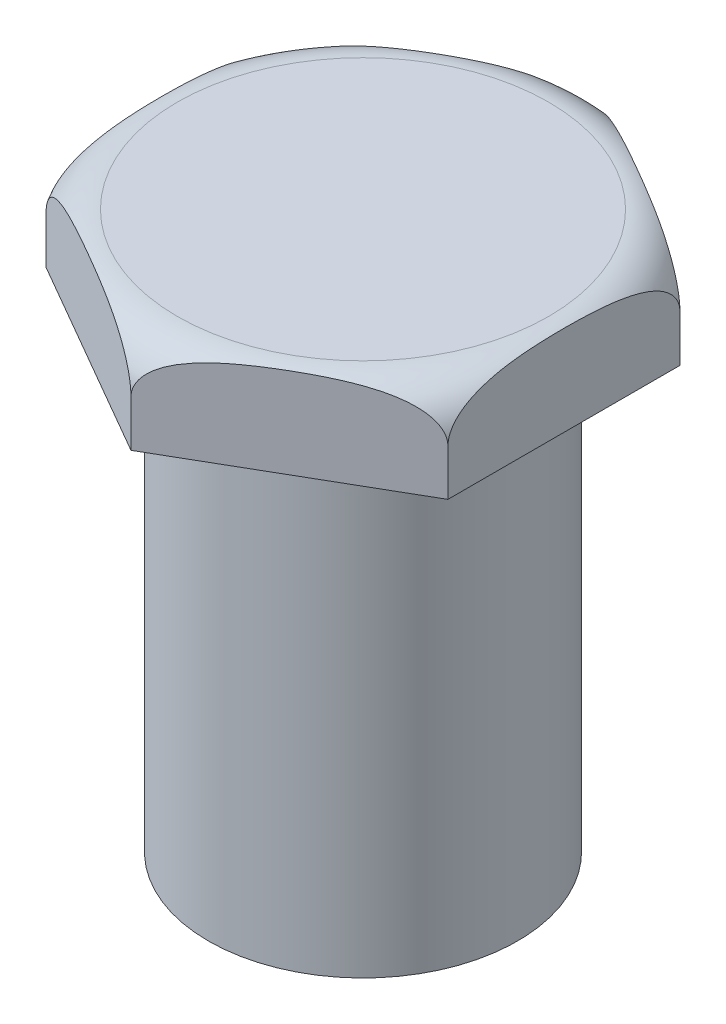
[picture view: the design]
ISO-10303-21;
HEADER;
FILE_DESCRIPTION(('STEP AP214'),'2;1');
FILE_NAME('part.step','',(''),(''),'','','');
FILE_SCHEMA(('AUTOMOTIVE_DESIGN { 1 0 10303 214 1 1 1 1 }'));
ENDSEC;
DATA;
#1=APPLICATION_CONTEXT('core data for automotive mechanical design processes');
#2=APPLICATION_PROTOCOL_DEFINITION('international standard','automotive_design',2000,#1);
#3=PRODUCT_CONTEXT('',#1,'mechanical');
#4=PRODUCT('Part','Part','',(#3));
#5=PRODUCT_RELATED_PRODUCT_CATEGORY('part','',(#4));
#6=PRODUCT_DEFINITION_FORMATION('','',#4);
#7=PRODUCT_DEFINITION_CONTEXT('part definition',#1,'design');
#8=PRODUCT_DEFINITION('design','',#6,#7);
#9=PRODUCT_DEFINITION_SHAPE('','',#8);
#10=(LENGTH_UNIT() NAMED_UNIT(*) SI_UNIT(.MILLI.,.METRE.));
#11=(NAMED_UNIT(*) PLANE_ANGLE_UNIT() SI_UNIT($,.RADIAN.));
#12=(NAMED_UNIT(*) SI_UNIT($,.STERADIAN.) SOLID_ANGLE_UNIT());
#13=UNCERTAINTY_MEASURE_WITH_UNIT(LENGTH_MEASURE(1.E-05),#10,'distance_accuracy_value','');
#14=(GEOMETRIC_REPRESENTATION_CONTEXT(3) GLOBAL_UNCERTAINTY_ASSIGNED_CONTEXT((#13)) GLOBAL_UNIT_ASSIGNED_CONTEXT((#10,
#11,#12)) REPRESENTATION_CONTEXT('',''));
#15=CARTESIAN_POINT('',(0.,0.,0.));
#16=DIRECTION('',(0.,0.,1.));
#17=DIRECTION('',(1.,0.,0.));
#18=AXIS2_PLACEMENT_3D('',#15,#16,#17);
#19=CARTESIAN_POINT('',(0.,15.,0.));
#20=DIRECTION('',(0.,-1.,0.));
#21=DIRECTION('',(0.,0.,-1.));
#22=AXIS2_PLACEMENT_3D('',#19,#20,#21);
#23=CYLINDRICAL_SURFACE('',#22,5.);
#24=CARTESIAN_POINT('',(0.,15.,0.));
#25=DIRECTION('',(0.,1.,0.));
#26=DIRECTION('',(0.,0.,1.));
#27=AXIS2_PLACEMENT_3D('',#24,#25,#26);
#28=CIRCLE('',#27,5.);
#29=CARTESIAN_POINT('',(0.,15.,5.));
#30=VERTEX_POINT('',#29);
#31=EDGE_CURVE('E11',#30,#30,#28,.T.);
#32=ORIENTED_EDGE('',*,*,#31,.F.);
#33=EDGE_LOOP('',(#32));
#34=FACE_BOUND('',#33,.T.);
#35=CARTESIAN_POINT('',(0.,0.,0.));
#36=DIRECTION('',(0.,1.,0.));
#37=DIRECTION('',(0.,0.,1.));
#38=AXIS2_PLACEMENT_3D('',#35,#36,#37);
#39=CIRCLE('',#38,5.);
#40=CARTESIAN_POINT('',(0.,0.,5.));
#41=VERTEX_POINT('',#40);
#42=EDGE_CURVE('E39',#41,#41,#39,.T.);
#43=ORIENTED_EDGE('',*,*,#42,.T.);
#44=EDGE_LOOP('',(#43));
#45=FACE_BOUND('',#44,.T.);
#46=ADVANCED_FACE('F32',(#34,#45),#23,.T.);
#47=CARTESIAN_POINT('',(0.,0.,0.));
#48=DIRECTION('',(0.,1.,0.));
#49=DIRECTION('',(0.,0.,1.));
#50=AXIS2_PLACEMENT_3D('',#47,#48,#49);
#51=PLANE('',#50);
#52=ORIENTED_EDGE('',*,*,#42,.F.);
#53=EDGE_LOOP('',(#52));
#54=FACE_BOUND('',#53,.T.);
#55=ADVANCED_FACE('F118',(#54),#51,.F.);
#56=CARTESIAN_POINT('',(0.,15.,7.50555349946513));
#57=DIRECTION('',(0.,1.,0.));
#58=DIRECTION('',(0.,0.,1.));
#59=AXIS2_PLACEMENT_3D('',#56,#57,#58);
#60=PLANE('',#59);
#61=DIRECTION('',(0.866025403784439,0.,0.5));
#62=VECTOR('',#61,1.);
#63=CARTESIAN_POINT('',(-6.49999999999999,15.,3.75277674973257));
#64=LINE('',#63,#62);
#65=CARTESIAN_POINT('',(-6.49999999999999,15.,3.75277674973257));
#66=VERTEX_POINT('',#65);
#67=CARTESIAN_POINT('',(0.,15.,7.50555349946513));
#68=VERTEX_POINT('',#67);
#69=EDGE_CURVE('E144',#66,#68,#64,.T.);
#70=ORIENTED_EDGE('',*,*,#69,.F.);
#71=DIRECTION('',(0.,0.,1.));
#72=VECTOR('',#71,1.);
#73=CARTESIAN_POINT('',(-6.5,15.,-3.75277674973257));
#74=LINE('',#73,#72);
#75=CARTESIAN_POINT('',(-6.5,15.,-3.75277674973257));
#76=VERTEX_POINT('',#75);
#77=EDGE_CURVE('E213',#76,#66,#74,.T.);
#78=ORIENTED_EDGE('',*,*,#77,.F.);
#79=DIRECTION('',(-0.866025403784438,0.,0.5));
#80=VECTOR('',#79,1.);
#81=CARTESIAN_POINT('',(0.,15.,-7.50555349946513));
#82=LINE('',#81,#80);
#83=CARTESIAN_POINT('',(0.,15.,-7.50555349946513));
#84=VERTEX_POINT('',#83);
#85=EDGE_CURVE('E211',#84,#76,#82,.T.);
#86=ORIENTED_EDGE('',*,*,#85,.F.);
#87=DIRECTION('',(-0.866025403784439,0.,-0.5));
#88=VECTOR('',#87,1.);
#89=CARTESIAN_POINT('',(6.5,15.,-3.75277674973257));
#90=LINE('',#89,#88);
#91=CARTESIAN_POINT('',(6.5,15.,-3.75277674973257));
#92=VERTEX_POINT('',#91);
#93=EDGE_CURVE('E103',#92,#84,#90,.T.);
#94=ORIENTED_EDGE('',*,*,#93,.F.);
#95=DIRECTION('',(0.,0.,-1.));
#96=VECTOR('',#95,1.);
#97=CARTESIAN_POINT('',(6.5,15.,3.75277674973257));
#98=LINE('',#97,#96);
#99=CARTESIAN_POINT('',(6.5,15.,3.75277674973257));
#100=VERTEX_POINT('',#99);
#101=EDGE_CURVE('E207',#100,#92,#98,.T.);
#102=ORIENTED_EDGE('',*,*,#101,.F.);
#103=DIRECTION('',(0.866025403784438,0.,-0.5));
#104=VECTOR('',#103,1.);
#105=CARTESIAN_POINT('',(0.,15.,7.50555349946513));
#106=LINE('',#105,#104);
#107=EDGE_CURVE('E202',#68,#100,#106,.T.);
#108=ORIENTED_EDGE('',*,*,#107,.F.);
#109=EDGE_LOOP('',(#70,#78,#86,#94,#102,#108));
#110=FACE_BOUND('',#109,.T.);
#111=ORIENTED_EDGE('',*,*,#31,.T.);
#112=EDGE_LOOP('',(#111));
#113=FACE_BOUND('',#112,.T.);
#114=ADVANCED_FACE('F120',(#110,#113),#60,.F.);
#115=CARTESIAN_POINT('',(-6.49999999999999,18.,3.75277674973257));
#116=DIRECTION('',(0.5,0.,-0.866025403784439));
#117=DIRECTION('',(-0.866025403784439,0.,-0.5));
#118=AXIS2_PLACEMENT_3D('',#115,#116,#117);
#119=PLANE('',#118);
#120=DIRECTION('',(0.,-1.,0.));
#121=VECTOR('',#120,1.);
#122=CARTESIAN_POINT('',(0.,18.,7.50555349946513));
#123=LINE('',#122,#121);
#124=CARTESIAN_POINT('',(0.,16.5,7.50555349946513));
#125=VERTEX_POINT('',#124);
#126=EDGE_CURVE('E113',#125,#68,#123,.T.);
#127=ORIENTED_EDGE('',*,*,#126,.F.);
#128=CARTESIAN_POINT('',(-2.30940165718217E-08,16.4998,7.5055534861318));
#129=CARTESIAN_POINT('',(8.75511159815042E-06,16.5221234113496,7.50555855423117));
#130=CARTESIAN_POINT('',(-0.000853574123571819,16.5444349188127,7.50506068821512));
#131=CARTESIAN_POINT('',(-0.00428008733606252,16.5888672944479,7.5030823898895));
#132=CARTESIAN_POINT('',(-0.00684304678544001,16.6109882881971,7.50160266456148));
#133=CARTESIAN_POINT('',(-0.0169647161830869,16.6764782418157,7.4957589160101));
#134=CARTESIAN_POINT('',(-0.0269577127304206,16.7193711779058,7.48998945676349));
#135=CARTESIAN_POINT('',(-0.0526687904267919,16.8026146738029,7.47514515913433));
#136=CARTESIAN_POINT('',(-0.0683721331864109,16.8429714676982,7.46607882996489));
#137=CARTESIAN_POINT('',(-0.104572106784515,16.9207748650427,7.44517876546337));
#138=CARTESIAN_POINT('',(-0.125079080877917,16.9582149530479,7.43333905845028));
#139=CARTESIAN_POINT('',(-0.183584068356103,17.0516963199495,7.39956118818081));
#140=CARTESIAN_POINT('',(-0.224631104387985,17.1051893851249,7.37586267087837));
#141=CARTESIAN_POINT('',(-0.313424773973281,17.2041374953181,7.32459762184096));
#142=CARTESIAN_POINT('',(-0.361187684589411,17.2495723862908,7.29702169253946));
#143=CARTESIAN_POINT('',(-0.45328633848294,17.3266674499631,7.24384850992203));
#144=CARTESIAN_POINT('',(-0.496980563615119,17.3593702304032,7.21862163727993));
#145=CARTESIAN_POINT('',(-0.586671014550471,17.4203032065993,7.16683883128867));
#146=CARTESIAN_POINT('',(-0.632668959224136,17.4485299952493,7.14028190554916));
#147=CARTESIAN_POINT('',(-0.726386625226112,17.5011025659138,7.0861739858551));
#148=CARTESIAN_POINT('',(-0.774109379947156,17.5254410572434,7.05862124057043));
#149=CARTESIAN_POINT('',(-0.87073173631,17.5706772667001,7.00283629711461));
#150=CARTESIAN_POINT('',(-0.919630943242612,17.5915761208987,6.9746043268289));
#151=CARTESIAN_POINT('',(-1.03884381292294,17.6384752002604,6.9057767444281));
#152=CARTESIAN_POINT('',(-1.10959806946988,17.6629774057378,6.86492675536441));
#153=CARTESIAN_POINT('',(-1.25225722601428,17.7070792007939,6.78256245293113));
#154=CARTESIAN_POINT('',(-1.32416270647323,17.7266762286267,6.74104780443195));
#155=CARTESIAN_POINT('',(-1.4688338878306,17.7618548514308,6.65752185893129));
#156=CARTESIAN_POINT('',(-1.54160091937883,17.7774290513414,6.61550979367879));
#157=CARTESIAN_POINT('',(-1.68761851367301,17.8052271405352,6.53120649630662));
#158=CARTESIAN_POINT('',(-1.76086916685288,17.8174503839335,6.48891521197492));
#159=CARTESIAN_POINT('',(-1.98171238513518,17.8500949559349,6.36141132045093));
#160=CARTESIAN_POINT('',(-2.12976388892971,17.8663490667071,6.27593374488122));
#161=CARTESIAN_POINT('',(-2.42614675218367,17.8912869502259,6.10481701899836));
#162=CARTESIAN_POINT('',(-2.57447770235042,17.8999780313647,6.01917810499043));
#163=CARTESIAN_POINT('',(-2.82610814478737,17.9100429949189,5.87389920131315));
#164=CARTESIAN_POINT('',(-2.92936804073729,17.9128390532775,5.81428207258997));
#165=CARTESIAN_POINT('',(-3.13591576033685,17.9160895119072,5.69503169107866));
#166=CARTESIAN_POINT('',(-3.23920358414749,17.9165438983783,5.63539843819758));
#167=CARTESIAN_POINT('',(-3.44547818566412,17.9151743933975,5.51630574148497));
#168=CARTESIAN_POINT('',(-3.54846499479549,17.9133568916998,5.45684627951));
#169=CARTESIAN_POINT('',(-3.75437898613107,17.9072298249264,5.33796178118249));
#170=CARTESIAN_POINT('',(-3.85730617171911,17.9029204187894,5.2785367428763));
#171=CARTESIAN_POINT('',(-4.05682053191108,17.8916511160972,5.16334707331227));
#172=CARTESIAN_POINT('',(-4.15341494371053,17.8848671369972,5.10757826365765));
#173=CARTESIAN_POINT('',(-4.34638627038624,17.8679880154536,4.99616621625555));
#174=CARTESIAN_POINT('',(-4.44276320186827,17.857893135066,4.94052296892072));
#175=CARTESIAN_POINT('',(-4.63526955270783,17.833461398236,4.82937937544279));
#176=CARTESIAN_POINT('',(-4.73139838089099,17.8191181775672,4.77387937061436));
#177=CARTESIAN_POINT('',(-4.92292696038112,17.7849926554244,4.66330029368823));
#178=CARTESIAN_POINT('',(-5.01832692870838,17.765212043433,4.6082210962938));
#179=CARTESIAN_POINT('',(-5.17682541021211,17.7262572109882,4.51671195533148));
#180=CARTESIAN_POINT('',(-5.24027601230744,17.7090036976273,4.4800787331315));
#181=CARTESIAN_POINT('',(-5.36631198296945,17.6707229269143,4.40731183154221));
#182=CARTESIAN_POINT('',(-5.42889757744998,17.649696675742,4.37117802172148));
#183=CARTESIAN_POINT('',(-5.55268628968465,17.6032086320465,4.29970857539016));
#184=CARTESIAN_POINT('',(-5.6138921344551,17.5777566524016,4.26437136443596));
#185=CARTESIAN_POINT('',(-5.73443040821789,17.5215557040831,4.19477855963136));
#186=CARTESIAN_POINT('',(-5.79376410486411,17.4908104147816,4.16052223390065));
#187=CARTESIAN_POINT('',(-5.91249548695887,17.421379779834,4.09197263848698));
#188=CARTESIAN_POINT('',(-5.97175929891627,17.3823839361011,4.05775666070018));
#189=CARTESIAN_POINT('',(-6.08568914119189,17.2961180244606,3.99197923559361));
#190=CARTESIAN_POINT('',(-6.14035696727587,17.2488512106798,3.96041675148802));
#191=CARTESIAN_POINT('',(-6.23181669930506,17.1556127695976,3.90761245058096));
#192=CARTESIAN_POINT('',(-6.26995888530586,17.1114270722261,3.88559104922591));
#193=CARTESIAN_POINT('',(-6.33977264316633,17.0166492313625,3.84528405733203));
#194=CARTESIAN_POINT('',(-6.3714551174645,16.9660681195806,3.82699217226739));
#195=CARTESIAN_POINT('',(-6.41909645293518,16.8721707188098,3.79948643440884));
#196=CARTESIAN_POINT('',(-6.43700615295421,16.8301800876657,3.78914626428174));
#197=CARTESIAN_POINT('',(-6.46659963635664,16.7433987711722,3.7720604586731));
#198=CARTESIAN_POINT('',(-6.47829790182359,16.6986148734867,3.7653064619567));
#199=CARTESIAN_POINT('',(-6.49091266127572,16.6278399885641,3.75802332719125));
#200=CARTESIAN_POINT('',(-6.49431146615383,16.602415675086,3.75606102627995));
#201=CARTESIAN_POINT('',(-6.49886334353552,16.5512668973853,3.75343299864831));
#202=CARTESIAN_POINT('',(-6.50001339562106,16.5255420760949,3.75276901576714));
#203=CARTESIAN_POINT('',(-6.49999997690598,16.4998,3.75277676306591));
#204=B_SPLINE_CURVE_WITH_KNOTS('',3,(#128,#129,#130,#131,#132,#133,#134,#135,#136,#137,#138,
#139,#140,#141,#142,#143,#144,#145,#146,#147,#148,#149,#150,#151,#152,#153,#154,#155,#156,#157,
#158,#159,#160,#161,#162,#163,#164,#165,#166,#167,#168,#169,#170,#171,#172,#173,#174,#175,#176,
#177,#178,#179,#180,#181,#182,#183,#184,#185,#186,#187,#188,#189,#190,#191,#192,#193,#194,#195,
#196,#197,#198,#199,#200,#201,#202,#203),.UNSPECIFIED.,.F.,.F.,(4,2,2,2,2,2,2,2,2,2,2,2,2,2,2,2,
2,2,2,2,2,2,2,2,2,2,2,2,2,2,2,2,2,2,2,2,2,4),(0.,0.0669247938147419,0.133801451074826,
0.266380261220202,0.398619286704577,0.531145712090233,0.744334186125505,0.958048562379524,
1.13816778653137,1.31842346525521,1.49901325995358,1.67954328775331,1.9352254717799,
2.19104090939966,2.44732331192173,2.70365507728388,3.21854516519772,3.73293714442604,
4.0907150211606,4.44849500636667,4.80527098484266,5.16202420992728,5.49721756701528,
5.83238440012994,6.16805589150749,6.50362320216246,6.72935456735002,6.95502581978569,
7.18020294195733,7.40522417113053,7.64105600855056,7.87679526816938,8.06336776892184,
8.24962272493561,8.38951558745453,8.52908083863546,8.60613662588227,8.68329583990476),.UNSPECIFIED.);
#205=CARTESIAN_POINT('',(-6.5,16.5,3.75277674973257));
#206=VERTEX_POINT('',#205);
#207=EDGE_CURVE('E137',#125,#206,#204,.T.);
#208=ORIENTED_EDGE('',*,*,#207,.T.);
#209=DIRECTION('',(0.,-1.,0.));
#210=VECTOR('',#209,1.);
#211=CARTESIAN_POINT('',(-6.49999999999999,18.,3.75277674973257));
#212=LINE('',#211,#210);
#213=EDGE_CURVE('E54',#206,#66,#212,.T.);
#214=ORIENTED_EDGE('',*,*,#213,.T.);
#215=ORIENTED_EDGE('',*,*,#69,.T.);
#216=EDGE_LOOP('',(#127,#208,#214,#215));
#217=FACE_BOUND('',#216,.T.);
#218=ADVANCED_FACE('F125',(#217),#119,.F.);
#219=CARTESIAN_POINT('',(0.,18.,7.50555349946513));
#220=DIRECTION('',(-0.5,0.,-0.866025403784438));
#221=DIRECTION('',(-0.866025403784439,0.,0.5));
#222=AXIS2_PLACEMENT_3D('',#219,#220,#221);
#223=PLANE('',#222);
#224=DIRECTION('',(0.,-1.,0.));
#225=VECTOR('',#224,1.);
#226=CARTESIAN_POINT('',(6.5,18.,3.75277674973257));
#227=LINE('',#226,#225);
#228=CARTESIAN_POINT('',(6.5,16.5,3.75277674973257));
#229=VERTEX_POINT('',#228);
#230=EDGE_CURVE('E107',#229,#100,#227,.T.);
#231=ORIENTED_EDGE('',*,*,#230,.F.);
#232=CARTESIAN_POINT('',(6.49999997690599,16.4998,3.7527767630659));
#233=CARTESIAN_POINT('',(6.5000087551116,16.5221234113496,3.75277169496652));
#234=CARTESIAN_POINT('',(6.49914642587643,16.5444349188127,3.75326956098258));
#235=CARTESIAN_POINT('',(6.49571991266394,16.5888672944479,3.75524785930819));
#236=CARTESIAN_POINT('',(6.49315695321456,16.6109882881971,3.75672758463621));
#237=CARTESIAN_POINT('',(6.48303528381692,16.6764782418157,3.76257133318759));
#238=CARTESIAN_POINT('',(6.47304228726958,16.7193711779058,3.76834079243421));
#239=CARTESIAN_POINT('',(6.44733120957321,16.8026146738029,3.78318509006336));
#240=CARTESIAN_POINT('',(6.43162786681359,16.8429714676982,3.79225141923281));
#241=CARTESIAN_POINT('',(6.39542789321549,16.9207748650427,3.81315148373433));
#242=CARTESIAN_POINT('',(6.37492091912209,16.9582149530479,3.82499119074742));
#243=CARTESIAN_POINT('',(6.3164159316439,17.0516963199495,3.85876906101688));
#244=CARTESIAN_POINT('',(6.27536889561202,17.1051893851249,3.88246757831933));
#245=CARTESIAN_POINT('',(6.18657522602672,17.2041374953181,3.93373262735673));
#246=CARTESIAN_POINT('',(6.1388123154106,17.2495723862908,3.96130855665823));
#247=CARTESIAN_POINT('',(6.04671366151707,17.3266674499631,4.01448173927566));
#248=CARTESIAN_POINT('',(6.00301943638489,17.3593702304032,4.03970861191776));
#249=CARTESIAN_POINT('',(5.91332898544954,17.4203032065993,4.09149141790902));
#250=CARTESIAN_POINT('',(5.86733104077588,17.4485299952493,4.11804834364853));
#251=CARTESIAN_POINT('',(5.7736133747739,17.5011025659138,4.1721562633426));
#252=CARTESIAN_POINT('',(5.72589062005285,17.5254410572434,4.19970900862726));
#253=CARTESIAN_POINT('',(5.62926826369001,17.5706772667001,4.25549395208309));
#254=CARTESIAN_POINT('',(5.5803690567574,17.5915761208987,4.28372592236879));
#255=CARTESIAN_POINT('',(5.46115618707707,17.6384752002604,4.35255350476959));
#256=CARTESIAN_POINT('',(5.39040193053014,17.6629774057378,4.39340349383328));
#257=CARTESIAN_POINT('',(5.24774277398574,17.7070792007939,4.47576779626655));
#258=CARTESIAN_POINT('',(5.17583729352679,17.7266762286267,4.51728244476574));
#259=CARTESIAN_POINT('',(5.03116611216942,17.7618548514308,4.60080839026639));
#260=CARTESIAN_POINT('',(4.9583990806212,17.7774290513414,4.64282045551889));
#261=CARTESIAN_POINT('',(4.81238148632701,17.8052271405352,4.72712375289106));
#262=CARTESIAN_POINT('',(4.73913083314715,17.8174503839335,4.76941503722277));
#263=CARTESIAN_POINT('',(4.51828761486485,17.8500949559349,4.89691892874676));
#264=CARTESIAN_POINT('',(4.37023611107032,17.8663490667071,4.98239650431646));
#265=CARTESIAN_POINT('',(4.07385324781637,17.8912869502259,5.15351323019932));
#266=CARTESIAN_POINT('',(3.92552229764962,17.8999780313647,5.23915214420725));
#267=CARTESIAN_POINT('',(3.67389185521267,17.9100429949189,5.38443104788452));
#268=CARTESIAN_POINT('',(3.57063195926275,17.9128390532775,5.4440481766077));
#269=CARTESIAN_POINT('',(3.36408423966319,17.9160895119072,5.56329855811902));
#270=CARTESIAN_POINT('',(3.26079641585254,17.9165438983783,5.6229318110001));
#271=CARTESIAN_POINT('',(3.05452181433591,17.9151743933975,5.74202450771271));
#272=CARTESIAN_POINT('',(2.95153500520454,17.9133568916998,5.80148396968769));
#273=CARTESIAN_POINT('',(2.74562101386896,17.9072298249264,5.9203684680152));
#274=CARTESIAN_POINT('',(2.64269382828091,17.9029204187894,5.97979350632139));
#275=CARTESIAN_POINT('',(2.44317946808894,17.8916511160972,6.09498317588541));
#276=CARTESIAN_POINT('',(2.34658505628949,17.8848671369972,6.15075198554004));
#277=CARTESIAN_POINT('',(2.15361372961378,17.8679880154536,6.26216403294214));
#278=CARTESIAN_POINT('',(2.05723679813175,17.857893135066,6.31780728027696));
#279=CARTESIAN_POINT('',(1.86473044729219,17.833461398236,6.4289508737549));
#280=CARTESIAN_POINT('',(1.76860161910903,17.8191181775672,6.48445087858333));
#281=CARTESIAN_POINT('',(1.57707303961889,17.7849926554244,6.59502995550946));
#282=CARTESIAN_POINT('',(1.48167307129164,17.765212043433,6.65010915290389));
#283=CARTESIAN_POINT('',(1.32317458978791,17.7262572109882,6.74161829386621));
#284=CARTESIAN_POINT('',(1.25972398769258,17.7090036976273,6.7782515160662));
#285=CARTESIAN_POINT('',(1.13368801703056,17.6707229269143,6.85101841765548));
#286=CARTESIAN_POINT('',(1.07110242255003,17.6496966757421,6.88715222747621));
#287=CARTESIAN_POINT('',(0.947313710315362,17.6032086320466,6.95862167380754));
#288=CARTESIAN_POINT('',(0.886107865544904,17.5777566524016,6.99395888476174));
#289=CARTESIAN_POINT('',(0.765569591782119,17.5215557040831,7.06355168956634));
#290=CARTESIAN_POINT('',(0.706235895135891,17.4908104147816,7.09780801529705));
#291=CARTESIAN_POINT('',(0.587504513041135,17.421379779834,7.16635761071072));
#292=CARTESIAN_POINT('',(0.528240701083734,17.3823839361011,7.20057358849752));
#293=CARTESIAN_POINT('',(0.41431085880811,17.2961180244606,7.26635101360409));
#294=CARTESIAN_POINT('',(0.359643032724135,17.2488512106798,7.29791349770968));
#295=CARTESIAN_POINT('',(0.268183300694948,17.1556127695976,7.35071779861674));
#296=CARTESIAN_POINT('',(0.230041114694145,17.1114270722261,7.37273919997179));
#297=CARTESIAN_POINT('',(0.160227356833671,17.0166492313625,7.41304619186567));
#298=CARTESIAN_POINT('',(0.128544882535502,16.9660681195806,7.43133807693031));
#299=CARTESIAN_POINT('',(0.0809035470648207,16.8721707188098,7.45884381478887));
#300=CARTESIAN_POINT('',(0.0629938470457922,16.8301800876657,7.46918398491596));
#301=CARTESIAN_POINT('',(0.0334003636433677,16.7433987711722,7.4862697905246));
#302=CARTESIAN_POINT('',(0.0217020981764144,16.6986148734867,7.493023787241));
#303=CARTESIAN_POINT('',(0.00908733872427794,16.6278399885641,7.50030692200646));
#304=CARTESIAN_POINT('',(0.00568853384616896,16.602415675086,7.50226922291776));
#305=CARTESIAN_POINT('',(0.0011366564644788,16.5512668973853,7.50489725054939));
#306=CARTESIAN_POINT('',(-1.3395621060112E-05,16.5255420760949,7.50556123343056));
#307=CARTESIAN_POINT('',(2.30940160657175E-08,16.4998,7.5055534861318));
#308=B_SPLINE_CURVE_WITH_KNOTS('',3,(#232,#233,#234,#235,#236,#237,#238,#239,#240,#241,#242,
#243,#244,#245,#246,#247,#248,#249,#250,#251,#252,#253,#254,#255,#256,#257,#258,#259,#260,#261,
#262,#263,#264,#265,#266,#267,#268,#269,#270,#271,#272,#273,#274,#275,#276,#277,#278,#279,#280,
#281,#282,#283,#284,#285,#286,#287,#288,#289,#290,#291,#292,#293,#294,#295,#296,#297,#298,#299,
#300,#301,#302,#303,#304,#305,#306,#307),.UNSPECIFIED.,.F.,.F.,(4,2,2,2,2,2,2,2,2,2,2,2,2,2,2,2,
2,2,2,2,2,2,2,2,2,2,2,2,2,2,2,2,2,2,2,2,2,4),(0.,0.0669247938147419,0.133801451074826,
0.266380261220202,0.398619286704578,0.531145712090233,0.744334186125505,0.958048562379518,
1.13816778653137,1.3184234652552,1.49901325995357,1.6795432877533,1.93522547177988,
2.19104090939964,2.44732331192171,2.70365507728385,3.21854516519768,3.732937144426,
4.09071502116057,4.44849500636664,4.80527098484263,5.16202420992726,5.49721756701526,
5.83238440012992,6.16805589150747,6.50362320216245,6.72935456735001,6.95502581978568,
7.18020294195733,7.40522417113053,7.64105600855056,7.87679526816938,8.06336776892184,
8.24962272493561,8.38951558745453,8.52908083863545,8.60613662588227,8.68329583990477),.UNSPECIFIED.);
#309=EDGE_CURVE('E145',#229,#125,#308,.T.);
#310=ORIENTED_EDGE('',*,*,#309,.T.);
#311=ORIENTED_EDGE('',*,*,#126,.T.);
#312=ORIENTED_EDGE('',*,*,#107,.T.);
#313=EDGE_LOOP('',(#231,#310,#311,#312));
#314=FACE_BOUND('',#313,.T.);
#315=ADVANCED_FACE('F133',(#314),#223,.F.);
#316=CARTESIAN_POINT('',(6.5,18.,3.75277674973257));
#317=DIRECTION('',(-1.,0.,0.));
#318=DIRECTION('',(0.,0.,1.));
#319=AXIS2_PLACEMENT_3D('',#316,#317,#318);
#320=PLANE('',#319);
#321=DIRECTION('',(0.,-1.,0.));
#322=VECTOR('',#321,1.);
#323=CARTESIAN_POINT('',(6.5,18.,-3.75277674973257));
#324=LINE('',#323,#322);
#325=CARTESIAN_POINT('',(6.5,16.5,-3.75277674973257));
#326=VERTEX_POINT('',#325);
#327=EDGE_CURVE('E105',#326,#92,#324,.T.);
#328=ORIENTED_EDGE('',*,*,#327,.F.);
#329=CARTESIAN_POINT('',(6.5,17.916164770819,0.));
#330=CARTESIAN_POINT('',(6.5,17.9161702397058,0.184620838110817));
#331=CARTESIAN_POINT('',(6.5,17.9134846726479,0.369242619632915));
#332=CARTESIAN_POINT('',(6.5,17.901956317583,0.738435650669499));
#333=CARTESIAN_POINT('',(6.5,17.8931097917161,0.923006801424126));
#334=CARTESIAN_POINT('',(6.5,17.8732973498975,1.19962800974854));
#335=CARTESIAN_POINT('',(6.5,17.8655891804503,1.29190964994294));
#336=CARTESIAN_POINT('',(6.5,17.8474791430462,1.47620468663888));
#337=CARTESIAN_POINT('',(6.5,17.8370775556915,1.56821811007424));
#338=CARTESIAN_POINT('',(6.5,17.8129836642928,1.7517216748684));
#339=CARTESIAN_POINT('',(6.5,17.7992948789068,1.84321226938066));
#340=CARTESIAN_POINT('',(6.5,17.7678579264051,2.02548339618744));
#341=CARTESIAN_POINT('',(6.5,17.7501107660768,2.11626409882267));
#342=CARTESIAN_POINT('',(6.5,17.7092536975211,2.29830317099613));
#343=CARTESIAN_POINT('',(6.5,17.6860553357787,2.38954207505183));
#344=CARTESIAN_POINT('',(6.5,17.63324600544,2.57011744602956));
#345=CARTESIAN_POINT('',(6.5,17.6036395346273,2.65945519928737));
#346=CARTESIAN_POINT('',(6.5,17.5366971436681,2.83449743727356));
#347=CARTESIAN_POINT('',(6.5,17.4994191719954,2.92022366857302));
#348=CARTESIAN_POINT('',(6.5,17.4151776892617,3.08669422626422));
#349=CARTESIAN_POINT('',(6.5,17.3682373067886,3.16744986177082));
#350=CARTESIAN_POINT('',(6.5,17.273971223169,3.30414339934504));
#351=CARTESIAN_POINT('',(6.5,17.2289569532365,3.36165541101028));
#352=CARTESIAN_POINT('',(6.5,17.1305998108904,3.46913285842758));
#353=CARTESIAN_POINT('',(6.5,17.0772729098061,3.51911241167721));
#354=CARTESIAN_POINT('',(6.5,16.9797811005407,3.5939921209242));
#355=CARTESIAN_POINT('',(6.5,16.9379107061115,3.62186137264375));
#356=CARTESIAN_POINT('',(6.5,16.8502519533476,3.67063936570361));
#357=CARTESIAN_POINT('',(6.5,16.8044661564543,3.69155261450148));
#358=CARTESIAN_POINT('',(6.5,16.7093393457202,3.72494989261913));
#359=CARTESIAN_POINT('',(6.5,16.6599674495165,3.73734784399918));
#360=CARTESIAN_POINT('',(6.5,16.5597492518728,3.75207921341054));
#361=CARTESIAN_POINT('',(6.5,16.5089044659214,3.75442263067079));
#362=CARTESIAN_POINT('',(6.5,16.4149572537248,3.74921423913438));
#363=CARTESIAN_POINT('',(6.5,16.3717735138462,3.74301038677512));
#364=CARTESIAN_POINT('',(6.5,16.2870406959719,3.72353813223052));
#365=CARTESIAN_POINT('',(6.5,16.2454922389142,3.71026707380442));
#366=CARTESIAN_POINT('',(6.5,16.1547728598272,3.67346258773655));
#367=CARTESIAN_POINT('',(6.5,16.1063121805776,3.64818779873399));
#368=CARTESIAN_POINT('',(6.5,16.0141478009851,3.59010876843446));
#369=CARTESIAN_POINT('',(6.5,15.9704529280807,3.55729089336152));
#370=CARTESIAN_POINT('',(6.5,15.868545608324,3.46926743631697));
#371=CARTESIAN_POINT('',(6.5,15.8131768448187,3.4107938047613));
#372=CARTESIAN_POINT('',(6.5,15.7120378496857,3.28614981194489));
#373=CARTESIAN_POINT('',(6.5,15.6662861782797,3.21996494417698));
#374=CARTESIAN_POINT('',(6.5,15.5874521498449,3.09008893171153));
#375=CARTESIAN_POINT('',(6.5,15.5535369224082,3.02689306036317));
#376=CARTESIAN_POINT('',(6.5,15.4912346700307,2.89780113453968));
#377=CARTESIAN_POINT('',(6.5,15.4628524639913,2.83190278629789));
#378=CARTESIAN_POINT('',(6.5,15.4107325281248,2.69812272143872));
#379=CARTESIAN_POINT('',(6.5,15.3870069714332,2.63023632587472));
#380=CARTESIAN_POINT('',(6.5,15.3435806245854,2.49324120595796));
#381=CARTESIAN_POINT('',(6.5,15.3238779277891,2.42413307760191));
#382=CARTESIAN_POINT('',(6.5,15.276110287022,2.23966515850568));
#383=CARTESIAN_POINT('',(6.5,15.2509772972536,2.12354880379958));
#384=CARTESIAN_POINT('',(6.5,15.2077542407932,1.88998867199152));
#385=CARTESIAN_POINT('',(6.5,15.1896690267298,1.77254403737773));
#386=CARTESIAN_POINT('',(6.5,15.1588642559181,1.53666129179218));
#387=CARTESIAN_POINT('',(6.5,15.1461587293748,1.4182213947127));
#388=CARTESIAN_POINT('',(6.5,15.1249216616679,1.18101147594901));
#389=CARTESIAN_POINT('',(6.5,15.1163890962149,1.06224154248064));
#390=CARTESIAN_POINT('',(6.5,15.1025365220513,0.823841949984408));
#391=CARTESIAN_POINT('',(6.5,15.097235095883,0.704211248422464));
#392=CARTESIAN_POINT('',(6.5,15.0893002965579,0.464857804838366));
#393=CARTESIAN_POINT('',(6.5,15.0866670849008,0.345135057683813));
#394=CARTESIAN_POINT('',(6.5,15.083745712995,0.105835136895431));
#395=CARTESIAN_POINT('',(6.5,15.0834541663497,-0.0137419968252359));
#396=CARTESIAN_POINT('',(6.5,15.085172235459,-0.252874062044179));
#397=CARTESIAN_POINT('',(6.5,15.0871817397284,-0.372428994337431));
#398=CARTESIAN_POINT('',(6.5,15.0943273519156,-0.632683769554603));
#399=CARTESIAN_POINT('',(6.5,15.0999550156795,-0.77337102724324));
#400=CARTESIAN_POINT('',(6.5,15.1156590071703,-1.05457418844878));
#401=CARTESIAN_POINT('',(6.5,15.1257373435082,-1.19508998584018));
#402=CARTESIAN_POINT('',(6.5,15.1517919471,-1.47476177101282));
#403=CARTESIAN_POINT('',(6.5,15.1677331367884,-1.61392089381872));
#404=CARTESIAN_POINT('',(6.5,15.207669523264,-1.89104271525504));
#405=CARTESIAN_POINT('',(6.5,15.2316590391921,-2.02900618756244));
#406=CARTESIAN_POINT('',(6.5,15.2853882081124,-2.27794573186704));
#407=CARTESIAN_POINT('',(6.5,15.3133124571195,-2.38930459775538));
#408=CARTESIAN_POINT('',(6.5,15.3789705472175,-2.60958719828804));
#409=CARTESIAN_POINT('',(6.5,15.4167355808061,-2.71850197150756));
#410=CARTESIAN_POINT('',(6.5,15.5055221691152,-2.93253903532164));
#411=CARTESIAN_POINT('',(6.5,15.5567057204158,-3.03759573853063));
#412=CARTESIAN_POINT('',(6.5,15.6759936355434,-3.23755456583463));
#413=CARTESIAN_POINT('',(6.5,15.7440000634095,-3.33251106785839));
#414=CARTESIAN_POINT('',(6.5,15.8593250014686,-3.45792492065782));
#415=CARTESIAN_POINT('',(6.5,15.898472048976,-3.49587027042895));
#416=CARTESIAN_POINT('',(6.5,15.981705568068,-3.56602982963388));
#417=CARTESIAN_POINT('',(6.5,16.0257929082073,-3.59824302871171));
#418=CARTESIAN_POINT('',(6.5,16.1193048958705,-3.65533489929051));
#419=CARTESIAN_POINT('',(6.5,16.1687869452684,-3.68012148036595));
#420=CARTESIAN_POINT('',(6.5,16.271639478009,-3.71957198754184));
#421=CARTESIAN_POINT('',(6.5,16.3250025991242,-3.73425455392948));
#422=CARTESIAN_POINT('',(6.5,16.4269596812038,-3.75074988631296));
#423=CARTESIAN_POINT('',(6.5,16.4753327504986,-3.75392369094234));
#424=CARTESIAN_POINT('',(6.5,16.5717811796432,-3.75088982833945));
#425=CARTESIAN_POINT('',(6.5,16.619856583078,-3.74468356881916));
#426=CARTESIAN_POINT('',(6.5,16.7084115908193,-3.7247866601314));
#427=CARTESIAN_POINT('',(6.5,16.7491169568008,-3.71206829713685));
#428=CARTESIAN_POINT('',(6.5,16.8281561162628,-3.68071832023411));
#429=CARTESIAN_POINT('',(6.5,16.8664893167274,-3.6620852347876));
#430=CARTESIAN_POINT('',(6.5,16.957527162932,-3.61006808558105));
#431=CARTESIAN_POINT('',(6.5,17.0086136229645,-3.57385525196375));
#432=CARTESIAN_POINT('',(6.5,17.1043814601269,-3.49377752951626));
#433=CARTESIAN_POINT('',(6.5,17.1490468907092,-3.44989416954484));
#434=CARTESIAN_POINT('',(6.5,17.2566010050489,-3.32963106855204));
#435=CARTESIAN_POINT('',(6.5,17.3149418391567,-3.24921629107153));
#436=CARTESIAN_POINT('',(6.5,17.4190885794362,-3.08073962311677));
#437=CARTESIAN_POINT('',(6.5,17.4648647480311,-2.99266022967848));
#438=CARTESIAN_POINT('',(6.5,17.5457391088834,-2.81341823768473));
#439=CARTESIAN_POINT('',(6.5,17.5809879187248,-2.72232216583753));
#440=CARTESIAN_POINT('',(6.5,17.6437177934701,-2.53745293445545));
#441=CARTESIAN_POINT('',(6.5,17.671190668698,-2.44367706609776));
#442=CARTESIAN_POINT('',(6.5,17.7199426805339,-2.25437631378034));
#443=CARTESIAN_POINT('',(6.5,17.7412102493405,-2.15884851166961));
#444=CARTESIAN_POINT('',(6.5,17.7787344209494,-1.96680386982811));
#445=CARTESIAN_POINT('',(6.5,17.7949893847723,-1.87028671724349));
#446=CARTESIAN_POINT('',(6.5,17.8308238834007,-1.6268636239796));
#447=CARTESIAN_POINT('',(6.5,17.847811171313,-1.47958130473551));
#448=CARTESIAN_POINT('',(6.5,17.8752058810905,-1.18439382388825));
#449=CARTESIAN_POINT('',(6.5,17.8856107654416,-1.03648844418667));
#450=CARTESIAN_POINT('',(6.5,17.9015712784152,-0.740511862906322));
#451=CARTESIAN_POINT('',(6.5,17.9071296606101,-0.592440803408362));
#452=CARTESIAN_POINT('',(6.5,17.9144237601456,-0.296246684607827));
#453=CARTESIAN_POINT('',(6.5,17.9161603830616,-0.14812364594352));
#454=CARTESIAN_POINT('',(6.5,17.916164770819,0.));
#455=B_SPLINE_CURVE_WITH_KNOTS('',3,(#329,#330,#331,#332,#333,#334,#335,#336,#337,#338,#339,
#340,#341,#342,#343,#344,#345,#346,#347,#348,#349,#350,#351,#352,#353,#354,#355,#356,#357,#358,
#359,#360,#361,#362,#363,#364,#365,#366,#367,#368,#369,#370,#371,#372,#373,#374,#375,#376,#377,
#378,#379,#380,#381,#382,#383,#384,#385,#386,#387,#388,#389,#390,#391,#392,#393,#394,#395,#396,
#397,#398,#399,#400,#401,#402,#403,#404,#405,#406,#407,#408,#409,#410,#411,#412,#413,#414,#415,
#416,#417,#418,#419,#420,#421,#422,#423,#424,#425,#426,#427,#428,#429,#430,#431,#432,#433,#434,
#435,#436,#437,#438,#439,#440,#441,#442,#443,#444,#445,#446,#447,#448,#449,#450,#451,#452,#453,
#454),.UNSPECIFIED.,.T.,.F.,(4,2,2,2,2,2,2,2,2,2,2,2,2,2,2,2,2,2,2,2,2,2,2,2,2,2,2,2,2,2,2,2,2,
2,2,2,2,2,2,2,2,2,2,2,2,2,2,2,2,2,2,2,2,2,2,2,2,2,2,2,2,2,4),(0.,0.553847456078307,
1.10803122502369,1.38581008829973,1.66356002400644,1.94101396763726,2.21839915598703,
2.50064095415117,2.78268528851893,3.06267257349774,3.34199729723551,3.56047429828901,
3.77853659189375,3.92890827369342,4.07918232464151,4.23095392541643,4.38257455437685,
4.51282785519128,4.64313014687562,4.80619619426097,4.96955932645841,5.20979375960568,
5.45048765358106,5.66533774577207,5.88037413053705,6.09596537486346,6.31145420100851,
6.66754668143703,7.02388391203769,7.38114482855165,7.73831800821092,8.09752640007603,
8.45675653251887,8.81546707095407,9.17416023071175,9.59650591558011,10.0190424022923,
10.4390909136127,10.8588435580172,11.2029497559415,11.5481602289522,11.8977472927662,
12.2453452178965,12.4084929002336,12.5716693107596,12.736792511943,12.9016102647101,
13.0461521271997,13.1906722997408,13.3180953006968,13.4455500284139,13.6323448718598,
13.8195958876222,14.1159628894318,14.4130253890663,14.705608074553,14.9984977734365,
15.2919300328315,15.5854581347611,16.0300038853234,16.4747209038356,16.9191850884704,
17.3635439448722),.UNSPECIFIED.);
#456=EDGE_CURVE('E87',#326,#229,#455,.T.);
#457=ORIENTED_EDGE('',*,*,#456,.T.);
#458=ORIENTED_EDGE('',*,*,#230,.T.);
#459=ORIENTED_EDGE('',*,*,#101,.T.);
#460=EDGE_LOOP('',(#328,#457,#458,#459));
#461=FACE_BOUND('',#460,.T.);
#462=ADVANCED_FACE('F177',(#461),#320,.F.);
#463=CARTESIAN_POINT('',(6.5,18.,-3.75277674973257));
#464=DIRECTION('',(-0.5,0.,0.866025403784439));
#465=DIRECTION('',(0.866025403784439,0.,0.5));
#466=AXIS2_PLACEMENT_3D('',#463,#464,#465);
#467=PLANE('',#466);
#468=DIRECTION('',(0.,-1.,0.));
#469=VECTOR('',#468,1.);
#470=CARTESIAN_POINT('',(0.,18.,-7.50555349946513));
#471=LINE('',#470,#469);
#472=CARTESIAN_POINT('',(0.,16.5,-7.50555349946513));
#473=VERTEX_POINT('',#472);
#474=EDGE_CURVE('E96',#473,#84,#471,.T.);
#475=ORIENTED_EDGE('',*,*,#474,.F.);
#476=CARTESIAN_POINT('',(2.30940085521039E-08,16.4998,-7.5055534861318));
#477=CARTESIAN_POINT('',(-8.75511160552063E-06,16.5221234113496,-7.50555855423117));
#478=CARTESIAN_POINT('',(0.000853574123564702,16.5444349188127,-7.50506068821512));
#479=CARTESIAN_POINT('',(0.00428008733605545,16.5888672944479,-7.5030823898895));
#480=CARTESIAN_POINT('',(0.00684304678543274,16.6109882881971,-7.50160266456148));
#481=CARTESIAN_POINT('',(0.0169647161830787,16.6764782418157,-7.4957589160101));
#482=CARTESIAN_POINT('',(0.0269577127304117,16.7193711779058,-7.48998945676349));
#483=CARTESIAN_POINT('',(0.0526687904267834,16.8026146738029,-7.47514515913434));
#484=CARTESIAN_POINT('',(0.0683721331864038,16.8429714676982,-7.46607882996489));
#485=CARTESIAN_POINT('',(0.104572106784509,16.9207748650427,-7.44517876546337));
#486=CARTESIAN_POINT('',(0.12507908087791,16.9582149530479,-7.43333905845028));
#487=CARTESIAN_POINT('',(0.183584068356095,17.0516963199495,-7.39956118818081));
#488=CARTESIAN_POINT('',(0.224631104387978,17.1051893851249,-7.37586267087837));
#489=CARTESIAN_POINT('',(0.313424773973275,17.2041374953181,-7.32459762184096));
#490=CARTESIAN_POINT('',(0.361187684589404,17.2495723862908,-7.29702169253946));
#491=CARTESIAN_POINT('',(0.453286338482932,17.3266674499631,-7.24384850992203));
#492=CARTESIAN_POINT('',(0.49698056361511,17.3593702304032,-7.21862163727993));
#493=CARTESIAN_POINT('',(0.586671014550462,17.4203032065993,-7.16683883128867));
#494=CARTESIAN_POINT('',(0.632668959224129,17.4485299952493,-7.14028190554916));
#495=CARTESIAN_POINT('',(0.726386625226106,17.5011025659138,-7.08617398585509));
#496=CARTESIAN_POINT('',(0.77410937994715,17.5254410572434,-7.05862124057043));
#497=CARTESIAN_POINT('',(0.870731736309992,17.5706772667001,-7.00283629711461));
#498=CARTESIAN_POINT('',(0.919630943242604,17.5915761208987,-6.9746043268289));
#499=CARTESIAN_POINT('',(1.03884381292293,17.6384752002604,-6.9057767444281));
#500=CARTESIAN_POINT('',(1.10959806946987,17.6629774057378,-6.86492675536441));
#501=CARTESIAN_POINT('',(1.25225722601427,17.7070792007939,-6.78256245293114));
#502=CARTESIAN_POINT('',(1.32416270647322,17.7266762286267,-6.74104780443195));
#503=CARTESIAN_POINT('',(1.46883388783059,17.7618548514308,-6.6575218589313));
#504=CARTESIAN_POINT('',(1.54160091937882,17.7774290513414,-6.6155097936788));
#505=CARTESIAN_POINT('',(1.68761851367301,17.8052271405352,-6.53120649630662));
#506=CARTESIAN_POINT('',(1.76086916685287,17.8174503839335,-6.48891521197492));
#507=CARTESIAN_POINT('',(1.98171238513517,17.8500949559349,-6.36141132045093));
#508=CARTESIAN_POINT('',(2.12976388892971,17.8663490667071,-6.27593374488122));
#509=CARTESIAN_POINT('',(2.42614675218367,17.8912869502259,-6.10481701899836));
#510=CARTESIAN_POINT('',(2.57447770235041,17.8999780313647,-6.01917810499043));
#511=CARTESIAN_POINT('',(2.82610814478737,17.9100429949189,-5.87389920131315));
#512=CARTESIAN_POINT('',(2.92936804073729,17.9128390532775,-5.81428207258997));
#513=CARTESIAN_POINT('',(3.13591576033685,17.9160895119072,-5.69503169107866));
#514=CARTESIAN_POINT('',(3.23920358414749,17.9165438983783,-5.63539843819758));
#515=CARTESIAN_POINT('',(3.44547818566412,17.9151743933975,-5.51630574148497));
#516=CARTESIAN_POINT('',(3.54846499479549,17.9133568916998,-5.45684627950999));
#517=CARTESIAN_POINT('',(3.75437898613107,17.9072298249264,-5.33796178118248));
#518=CARTESIAN_POINT('',(3.85730617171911,17.9029204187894,-5.2785367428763));
#519=CARTESIAN_POINT('',(4.05682053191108,17.8916511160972,-5.16334707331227));
#520=CARTESIAN_POINT('',(4.15341494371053,17.8848671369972,-5.10757826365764));
#521=CARTESIAN_POINT('',(4.34638627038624,17.8679880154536,-4.99616621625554));
#522=CARTESIAN_POINT('',(4.44276320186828,17.857893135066,-4.94052296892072));
#523=CARTESIAN_POINT('',(4.63526955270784,17.833461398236,-4.82937937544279));
#524=CARTESIAN_POINT('',(4.731398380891,17.8191181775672,-4.77387937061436));
#525=CARTESIAN_POINT('',(4.92292696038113,17.7849926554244,-4.66330029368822));
#526=CARTESIAN_POINT('',(5.01832692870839,17.765212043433,-4.60822109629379));
#527=CARTESIAN_POINT('',(5.17682541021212,17.7262572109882,-4.51671195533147));
#528=CARTESIAN_POINT('',(5.24027601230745,17.7090036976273,-4.48007873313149));
#529=CARTESIAN_POINT('',(5.36631198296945,17.6707229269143,-4.4073118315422));
#530=CARTESIAN_POINT('',(5.42889757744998,17.649696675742,-4.37117802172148));
#531=CARTESIAN_POINT('',(5.55268628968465,17.6032086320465,-4.29970857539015));
#532=CARTESIAN_POINT('',(5.61389213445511,17.5777566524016,-4.26437136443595));
#533=CARTESIAN_POINT('',(5.73443040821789,17.5215557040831,-4.19477855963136));
#534=CARTESIAN_POINT('',(5.79376410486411,17.4908104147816,-4.16052223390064));
#535=CARTESIAN_POINT('',(5.91249548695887,17.421379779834,-4.09197263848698));
#536=CARTESIAN_POINT('',(5.97175929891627,17.3823839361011,-4.05775666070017));
#537=CARTESIAN_POINT('',(6.0856891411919,17.2961180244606,-3.99197923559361));
#538=CARTESIAN_POINT('',(6.14035696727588,17.2488512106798,-3.96041675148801));
#539=CARTESIAN_POINT('',(6.23181669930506,17.1556127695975,-3.90761245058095));
#540=CARTESIAN_POINT('',(6.26995888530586,17.1114270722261,-3.88559104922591));
#541=CARTESIAN_POINT('',(6.33977264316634,17.0166492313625,-3.84528405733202));
#542=CARTESIAN_POINT('',(6.37145511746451,16.9660681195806,-3.82699217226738));
#543=CARTESIAN_POINT('',(6.41909645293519,16.8721707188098,-3.79948643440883));
#544=CARTESIAN_POINT('',(6.43700615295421,16.8301800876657,-3.78914626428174));
#545=CARTESIAN_POINT('',(6.46659963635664,16.7433987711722,-3.77206045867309));
#546=CARTESIAN_POINT('',(6.47829790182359,16.6986148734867,-3.76530646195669));
#547=CARTESIAN_POINT('',(6.49091266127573,16.6278399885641,-3.75802332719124));
#548=CARTESIAN_POINT('',(6.49431146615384,16.602415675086,-3.75606102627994));
#549=CARTESIAN_POINT('',(6.49886334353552,16.5512668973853,-3.75343299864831));
#550=CARTESIAN_POINT('',(6.50001339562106,16.5255420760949,-3.75276901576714));
#551=CARTESIAN_POINT('',(6.49999997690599,16.4998,-3.7527767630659));
#552=B_SPLINE_CURVE_WITH_KNOTS('',3,(#476,#477,#478,#479,#480,#481,#482,#483,#484,#485,#486,
#487,#488,#489,#490,#491,#492,#493,#494,#495,#496,#497,#498,#499,#500,#501,#502,#503,#504,#505,
#506,#507,#508,#509,#510,#511,#512,#513,#514,#515,#516,#517,#518,#519,#520,#521,#522,#523,#524,
#525,#526,#527,#528,#529,#530,#531,#532,#533,#534,#535,#536,#537,#538,#539,#540,#541,#542,#543,
#544,#545,#546,#547,#548,#549,#550,#551),.UNSPECIFIED.,.F.,.F.,(4,2,2,2,2,2,2,2,2,2,2,2,2,2,2,2,
2,2,2,2,2,2,2,2,2,2,2,2,2,2,2,2,2,2,2,2,2,4),(0.,0.066924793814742,0.133801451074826,
0.266380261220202,0.398619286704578,0.531145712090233,0.744334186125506,0.958048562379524,
1.13816778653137,1.31842346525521,1.49901325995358,1.67954328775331,1.9352254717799,
2.19104090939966,2.44732331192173,2.70365507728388,3.21854516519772,3.73293714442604,
4.09071502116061,4.44849500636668,4.80527098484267,5.16202420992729,5.49721756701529,
5.83238440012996,6.1680558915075,6.50362320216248,6.72935456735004,6.9550258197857,
7.18020294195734,7.40522417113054,7.64105600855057,7.8767952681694,8.06336776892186,
8.24962272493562,8.38951558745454,8.52908083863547,8.60613662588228,8.68329583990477),.UNSPECIFIED.);
#553=EDGE_CURVE('E84',#473,#326,#552,.T.);
#554=ORIENTED_EDGE('',*,*,#553,.T.);
#555=ORIENTED_EDGE('',*,*,#327,.T.);
#556=ORIENTED_EDGE('',*,*,#93,.T.);
#557=EDGE_LOOP('',(#475,#554,#555,#556));
#558=FACE_BOUND('',#557,.T.);
#559=ADVANCED_FACE('F101',(#558),#467,.F.);
#560=CARTESIAN_POINT('',(0.,18.,-7.50555349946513));
#561=DIRECTION('',(0.5,0.,0.866025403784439));
#562=DIRECTION('',(0.866025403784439,0.,-0.5));
#563=AXIS2_PLACEMENT_3D('',#560,#561,#562);
#564=PLANE('',#563);
#565=DIRECTION('',(0.,-1.,0.));
#566=VECTOR('',#565,1.);
#567=CARTESIAN_POINT('',(-6.5,18.,-3.75277674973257));
#568=LINE('',#567,#566);
#569=CARTESIAN_POINT('',(-6.5,16.5,-3.75277674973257));
#570=VERTEX_POINT('',#569);
#571=EDGE_CURVE('E98',#570,#76,#568,.T.);
#572=ORIENTED_EDGE('',*,*,#571,.F.);
#573=CARTESIAN_POINT('',(-6.49999997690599,16.4998,-3.7527767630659));
#574=CARTESIAN_POINT('',(-6.5000087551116,16.5221234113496,-3.75277169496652));
#575=CARTESIAN_POINT('',(-6.49914642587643,16.5444349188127,-3.75326956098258));
#576=CARTESIAN_POINT('',(-6.49571991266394,16.5888672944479,-3.75524785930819));
#577=CARTESIAN_POINT('',(-6.49315695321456,16.6109882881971,-3.75672758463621));
#578=CARTESIAN_POINT('',(-6.48303528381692,16.6764782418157,-3.76257133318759));
#579=CARTESIAN_POINT('',(-6.47304228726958,16.7193711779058,-3.76834079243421));
#580=CARTESIAN_POINT('',(-6.44733120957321,16.8026146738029,-3.78318509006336));
#581=CARTESIAN_POINT('',(-6.43162786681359,16.8429714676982,-3.79225141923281));
#582=CARTESIAN_POINT('',(-6.39542789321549,16.9207748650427,-3.81315148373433));
#583=CARTESIAN_POINT('',(-6.37492091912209,16.9582149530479,-3.82499119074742));
#584=CARTESIAN_POINT('',(-6.3164159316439,17.0516963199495,-3.85876906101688));
#585=CARTESIAN_POINT('',(-6.27536889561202,17.1051893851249,-3.88246757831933));
#586=CARTESIAN_POINT('',(-6.18657522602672,17.2041374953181,-3.93373262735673));
#587=CARTESIAN_POINT('',(-6.13881231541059,17.2495723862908,-3.96130855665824));
#588=CARTESIAN_POINT('',(-6.04671366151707,17.3266674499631,-4.01448173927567));
#589=CARTESIAN_POINT('',(-6.00301943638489,17.3593702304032,-4.03970861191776));
#590=CARTESIAN_POINT('',(-5.91332898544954,17.4203032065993,-4.09149141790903));
#591=CARTESIAN_POINT('',(-5.86733104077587,17.4485299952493,-4.11804834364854));
#592=CARTESIAN_POINT('',(-5.77361337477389,17.5011025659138,-4.1721562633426));
#593=CARTESIAN_POINT('',(-5.72589062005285,17.5254410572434,-4.19970900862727));
#594=CARTESIAN_POINT('',(-5.62926826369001,17.5706772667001,-4.25549395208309));
#595=CARTESIAN_POINT('',(-5.58036905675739,17.5915761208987,-4.28372592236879));
#596=CARTESIAN_POINT('',(-5.46115618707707,17.6384752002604,-4.3525535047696));
#597=CARTESIAN_POINT('',(-5.39040193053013,17.6629774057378,-4.39340349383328));
#598=CARTESIAN_POINT('',(-5.24774277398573,17.7070792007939,-4.47576779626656));
#599=CARTESIAN_POINT('',(-5.17583729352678,17.7266762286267,-4.51728244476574));
#600=CARTESIAN_POINT('',(-5.03116611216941,17.7618548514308,-4.6008083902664));
#601=CARTESIAN_POINT('',(-4.95839908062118,17.7774290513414,-4.6428204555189));
#602=CARTESIAN_POINT('',(-4.812381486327,17.8052271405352,-4.72712375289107));
#603=CARTESIAN_POINT('',(-4.73913083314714,17.8174503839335,-4.76941503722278));
#604=CARTESIAN_POINT('',(-4.51828761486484,17.8500949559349,-4.89691892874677));
#605=CARTESIAN_POINT('',(-4.3702361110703,17.8663490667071,-4.98239650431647));
#606=CARTESIAN_POINT('',(-4.07385324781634,17.8912869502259,-5.15351323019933));
#607=CARTESIAN_POINT('',(-3.9255222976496,17.8999780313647,-5.23915214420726));
#608=CARTESIAN_POINT('',(-3.67389185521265,17.9100429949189,-5.38443104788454));
#609=CARTESIAN_POINT('',(-3.57063195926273,17.9128390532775,-5.44404817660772));
#610=CARTESIAN_POINT('',(-3.36408423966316,17.9160895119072,-5.56329855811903));
#611=CARTESIAN_POINT('',(-3.26079641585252,17.9165438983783,-5.62293181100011));
#612=CARTESIAN_POINT('',(-3.05452181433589,17.9151743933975,-5.74202450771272));
#613=CARTESIAN_POINT('',(-2.95153500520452,17.9133568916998,-5.8014839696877));
#614=CARTESIAN_POINT('',(-2.74562101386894,17.9072298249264,-5.92036846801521));
#615=CARTESIAN_POINT('',(-2.6426938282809,17.9029204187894,-5.97979350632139));
#616=CARTESIAN_POINT('',(-2.44317946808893,17.8916511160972,-6.09498317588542));
#617=CARTESIAN_POINT('',(-2.34658505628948,17.8848671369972,-6.15075198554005));
#618=CARTESIAN_POINT('',(-2.15361372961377,17.8679880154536,-6.26216403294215));
#619=CARTESIAN_POINT('',(-2.05723679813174,17.857893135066,-6.31780728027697));
#620=CARTESIAN_POINT('',(-1.86473044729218,17.833461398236,-6.4289508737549));
#621=CARTESIAN_POINT('',(-1.76860161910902,17.8191181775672,-6.48445087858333));
#622=CARTESIAN_POINT('',(-1.57707303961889,17.7849926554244,-6.59502995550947));
#623=CARTESIAN_POINT('',(-1.48167307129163,17.765212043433,-6.65010915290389));
#624=CARTESIAN_POINT('',(-1.3231745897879,17.7262572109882,-6.74161829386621));
#625=CARTESIAN_POINT('',(-1.25972398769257,17.7090036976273,-6.7782515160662));
#626=CARTESIAN_POINT('',(-1.13368801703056,17.6707229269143,-6.85101841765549));
#627=CARTESIAN_POINT('',(-1.07110242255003,17.6496966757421,-6.88715222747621));
#628=CARTESIAN_POINT('',(-0.947313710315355,17.6032086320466,-6.95862167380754));
#629=CARTESIAN_POINT('',(-0.886107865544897,17.5777566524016,-6.99395888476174));
#630=CARTESIAN_POINT('',(-0.765569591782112,17.5215557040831,-7.06355168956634));
#631=CARTESIAN_POINT('',(-0.706235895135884,17.4908104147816,-7.09780801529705));
#632=CARTESIAN_POINT('',(-0.587504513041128,17.421379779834,-7.16635761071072));
#633=CARTESIAN_POINT('',(-0.528240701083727,17.3823839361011,-7.20057358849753));
#634=CARTESIAN_POINT('',(-0.414310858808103,17.2961180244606,-7.26635101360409));
#635=CARTESIAN_POINT('',(-0.359643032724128,17.2488512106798,-7.29791349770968));
#636=CARTESIAN_POINT('',(-0.268183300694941,17.1556127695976,-7.35071779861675));
#637=CARTESIAN_POINT('',(-0.230041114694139,17.1114270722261,-7.37273919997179));
#638=CARTESIAN_POINT('',(-0.160227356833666,17.0166492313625,-7.41304619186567));
#639=CARTESIAN_POINT('',(-0.128544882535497,16.9660681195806,-7.43133807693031));
#640=CARTESIAN_POINT('',(-0.0809035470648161,16.8721707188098,-7.45884381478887));
#641=CARTESIAN_POINT('',(-0.0629938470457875,16.8301800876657,-7.46918398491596));
#642=CARTESIAN_POINT('',(-0.0334003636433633,16.7433987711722,-7.48626979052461));
#643=CARTESIAN_POINT('',(-0.0217020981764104,16.6986148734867,-7.493023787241));
#644=CARTESIAN_POINT('',(-0.00908733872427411,16.6278399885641,-7.50030692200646));
#645=CARTESIAN_POINT('',(-0.00568853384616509,16.602415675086,-7.50226922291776));
#646=CARTESIAN_POINT('',(-0.00113665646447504,16.5512668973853,-7.50489725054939));
#647=CARTESIAN_POINT('',(1.33956210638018E-05,16.5255420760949,-7.50556123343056));
#648=CARTESIAN_POINT('',(-2.30940125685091E-08,16.4998,-7.5055534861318));
#649=B_SPLINE_CURVE_WITH_KNOTS('',3,(#573,#574,#575,#576,#577,#578,#579,#580,#581,#582,#583,
#584,#585,#586,#587,#588,#589,#590,#591,#592,#593,#594,#595,#596,#597,#598,#599,#600,#601,#602,
#603,#604,#605,#606,#607,#608,#609,#610,#611,#612,#613,#614,#615,#616,#617,#618,#619,#620,#621,
#622,#623,#624,#625,#626,#627,#628,#629,#630,#631,#632,#633,#634,#635,#636,#637,#638,#639,#640,
#641,#642,#643,#644,#645,#646,#647,#648),.UNSPECIFIED.,.F.,.F.,(4,2,2,2,2,2,2,2,2,2,2,2,2,2,2,2,
2,2,2,2,2,2,2,2,2,2,2,2,2,2,2,2,2,2,2,2,2,4),(0.,0.0669247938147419,0.133801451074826,
0.266380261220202,0.398619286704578,0.531145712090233,0.744334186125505,0.958048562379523,
1.13816778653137,1.31842346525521,1.49901325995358,1.67954328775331,1.93522547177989,
2.19104090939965,2.44732331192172,2.70365507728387,3.21854516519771,3.73293714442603,
4.09071502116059,4.44849500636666,4.80527098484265,5.16202420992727,5.49721756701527,
5.83238440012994,6.16805589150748,6.50362320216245,6.72935456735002,6.95502581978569,
7.18020294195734,7.40522417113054,7.64105600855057,7.87679526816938,8.06336776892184,
8.24962272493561,8.38951558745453,8.52908083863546,8.60613662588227,8.68329583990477),.UNSPECIFIED.);
#650=EDGE_CURVE('E46',#570,#473,#649,.T.);
#651=ORIENTED_EDGE('',*,*,#650,.T.);
#652=ORIENTED_EDGE('',*,*,#474,.T.);
#653=ORIENTED_EDGE('',*,*,#85,.T.);
#654=EDGE_LOOP('',(#572,#651,#652,#653));
#655=FACE_BOUND('',#654,.T.);
#656=ADVANCED_FACE('F94',(#655),#564,.F.);
#657=CARTESIAN_POINT('',(-6.5,18.,-3.75277674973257));
#658=DIRECTION('',(1.,0.,0.));
#659=DIRECTION('',(0.,0.,-1.));
#660=AXIS2_PLACEMENT_3D('',#657,#658,#659);
#661=PLANE('',#660);
#662=ORIENTED_EDGE('',*,*,#213,.F.);
#663=CARTESIAN_POINT('',(-6.50000000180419,17.9161647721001,0.));
#664=CARTESIAN_POINT('',(-6.50000000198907,17.9161702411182,-0.184620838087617));
#665=CARTESIAN_POINT('',(-6.5000000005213,17.9134846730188,-0.369242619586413));
#666=CARTESIAN_POINT('',(-6.49999999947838,17.9019563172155,-0.738435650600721));
#667=CARTESIAN_POINT('',(-6.49999999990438,17.893109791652,-0.923006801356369));
#668=CARTESIAN_POINT('',(-6.50000000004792,17.8732973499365,-1.19962800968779));
#669=CARTESIAN_POINT('',(-6.50000000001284,17.8655891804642,-1.29190964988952));
#670=CARTESIAN_POINT('',(-6.49999999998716,17.847479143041,-1.476204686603));
#671=CARTESIAN_POINT('',(-6.49999999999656,17.8370775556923,-1.56821811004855));
#672=CARTESIAN_POINT('',(-6.50000000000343,17.8129836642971,-1.75172167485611));
#673=CARTESIAN_POINT('',(-6.50000000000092,17.799294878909,-1.8432122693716));
#674=CARTESIAN_POINT('',(-6.49999999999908,17.7678579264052,-2.02548339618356));
#675=CARTESIAN_POINT('',(-6.49999999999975,17.7501107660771,-2.11626409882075));
#676=CARTESIAN_POINT('',(-6.50000000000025,17.7092536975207,-2.29830317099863));
#677=CARTESIAN_POINT('',(-6.50000000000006,17.6860553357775,-2.38954207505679));
#678=CARTESIAN_POINT('',(-6.49999999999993,17.6332460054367,-2.57011744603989));
#679=CARTESIAN_POINT('',(-6.49999999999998,17.6036395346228,-2.6594551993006));
#680=CARTESIAN_POINT('',(-6.50000000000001,17.5366971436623,-2.8344974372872));
#681=CARTESIAN_POINT('',(-6.5,17.4994191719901,-2.92022366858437));
#682=CARTESIAN_POINT('',(-6.49999999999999,17.4151776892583,-3.08669422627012));
#683=CARTESIAN_POINT('',(-6.49999999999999,17.3682373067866,-3.16744986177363));
#684=CARTESIAN_POINT('',(-6.5,17.2739712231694,-3.30414339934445));
#685=CARTESIAN_POINT('',(-6.5,17.2289569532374,-3.36165541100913));
#686=CARTESIAN_POINT('',(-6.5,17.1305998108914,-3.46913285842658));
#687=CARTESIAN_POINT('',(-6.5,17.0772729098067,-3.51911241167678));
#688=CARTESIAN_POINT('',(-6.5,16.9797811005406,-3.5939921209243));
#689=CARTESIAN_POINT('',(-6.5,16.9379107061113,-3.62186137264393));
#690=CARTESIAN_POINT('',(-6.5,16.8502519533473,-3.67063936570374));
#691=CARTESIAN_POINT('',(-6.5,16.8044661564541,-3.69155261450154));
#692=CARTESIAN_POINT('',(-6.5,16.7093393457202,-3.72494989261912));
#693=CARTESIAN_POINT('',(-6.5,16.6599674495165,-3.73734784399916));
#694=CARTESIAN_POINT('',(-6.5,16.5597492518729,-3.75207921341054));
#695=CARTESIAN_POINT('',(-6.5,16.5089044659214,-3.7544226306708));
#696=CARTESIAN_POINT('',(-6.5,16.4149572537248,-3.74921423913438));
#697=CARTESIAN_POINT('',(-6.5,16.3717735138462,-3.74301038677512));
#698=CARTESIAN_POINT('',(-6.5,16.2870406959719,-3.72353813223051));
#699=CARTESIAN_POINT('',(-6.5,16.2454922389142,-3.71026707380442));
#700=CARTESIAN_POINT('',(-6.5,16.1547728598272,-3.67346258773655));
#701=CARTESIAN_POINT('',(-6.5,16.1063121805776,-3.64818779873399));
#702=CARTESIAN_POINT('',(-6.5,16.0141478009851,-3.59010876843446));
#703=CARTESIAN_POINT('',(-6.5,15.9704529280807,-3.55729089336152));
#704=CARTESIAN_POINT('',(-6.5,15.868545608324,-3.46926743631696));
#705=CARTESIAN_POINT('',(-6.5,15.8131768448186,-3.41079380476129));
#706=CARTESIAN_POINT('',(-6.5,15.7120378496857,-3.28614981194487));
#707=CARTESIAN_POINT('',(-6.5,15.6662861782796,-3.21996494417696));
#708=CARTESIAN_POINT('',(-6.5,15.5874521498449,-3.09008893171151));
#709=CARTESIAN_POINT('',(-6.5,15.5535369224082,-3.02689306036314));
#710=CARTESIAN_POINT('',(-6.5,15.4912346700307,-2.89780113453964));
#711=CARTESIAN_POINT('',(-6.5,15.4628524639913,-2.83190278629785));
#712=CARTESIAN_POINT('',(-6.5,15.4107325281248,-2.69812272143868));
#713=CARTESIAN_POINT('',(-6.5,15.3870069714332,-2.63023632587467));
#714=CARTESIAN_POINT('',(-6.5,15.3435806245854,-2.49324120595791));
#715=CARTESIAN_POINT('',(-6.5,15.3238779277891,-2.42413307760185));
#716=CARTESIAN_POINT('',(-6.5,15.276110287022,-2.23966515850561));
#717=CARTESIAN_POINT('',(-6.5,15.2509772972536,-2.1235488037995));
#718=CARTESIAN_POINT('',(-6.5,15.2077542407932,-1.88998867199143));
#719=CARTESIAN_POINT('',(-6.5,15.1896690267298,-1.77254403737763));
#720=CARTESIAN_POINT('',(-6.5,15.1588642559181,-1.53666129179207));
#721=CARTESIAN_POINT('',(-6.5,15.1461587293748,-1.41822139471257));
#722=CARTESIAN_POINT('',(-6.5,15.1249216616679,-1.18101147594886));
#723=CARTESIAN_POINT('',(-6.5,15.1163890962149,-1.06224154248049));
#724=CARTESIAN_POINT('',(-6.5,15.1025365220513,-0.823841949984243));
#725=CARTESIAN_POINT('',(-6.5,15.097235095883,-0.704211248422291));
#726=CARTESIAN_POINT('',(-6.5,15.0893002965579,-0.464857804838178));
#727=CARTESIAN_POINT('',(-6.5,15.0866670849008,-0.345135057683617));
#728=CARTESIAN_POINT('',(-6.5,15.083745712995,-0.105835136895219));
#729=CARTESIAN_POINT('',(-6.49999999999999,15.0834541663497,0.0137419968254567));
#730=CARTESIAN_POINT('',(-6.49999999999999,15.085172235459,0.252874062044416));
#731=CARTESIAN_POINT('',(-6.49999999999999,15.0871817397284,0.372428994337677));
#732=CARTESIAN_POINT('',(-6.49999999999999,15.0943273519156,0.632683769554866));
#733=CARTESIAN_POINT('',(-6.49999999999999,15.0999550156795,0.773371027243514));
#734=CARTESIAN_POINT('',(-6.49999999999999,15.1156590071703,1.05457418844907));
#735=CARTESIAN_POINT('',(-6.49999999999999,15.1257373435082,1.19508998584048));
#736=CARTESIAN_POINT('',(-6.49999999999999,15.1517919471,1.47476177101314));
#737=CARTESIAN_POINT('',(-6.49999999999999,15.1677331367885,1.61392089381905));
#738=CARTESIAN_POINT('',(-6.49999999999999,15.207669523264,1.89104271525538));
#739=CARTESIAN_POINT('',(-6.49999999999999,15.2316590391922,2.02900618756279));
#740=CARTESIAN_POINT('',(-6.49999999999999,15.2853882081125,2.27794573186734));
#741=CARTESIAN_POINT('',(-6.49999999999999,15.3133124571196,2.38930459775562));
#742=CARTESIAN_POINT('',(-6.49999999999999,15.3789705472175,2.60958719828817));
#743=CARTESIAN_POINT('',(-6.49999999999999,15.4167355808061,2.71850197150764));
#744=CARTESIAN_POINT('',(-6.49999999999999,15.5055221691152,2.93253903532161));
#745=CARTESIAN_POINT('',(-6.49999999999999,15.5567057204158,3.03759573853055));
#746=CARTESIAN_POINT('',(-6.49999999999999,15.6759936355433,3.23755456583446));
#747=CARTESIAN_POINT('',(-6.49999999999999,15.7440000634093,3.33251106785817));
#748=CARTESIAN_POINT('',(-6.49999999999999,15.8593250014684,3.45792492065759));
#749=CARTESIAN_POINT('',(-6.49999999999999,15.8984720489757,3.49587027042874));
#750=CARTESIAN_POINT('',(-6.49999999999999,15.9817055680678,3.56602982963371));
#751=CARTESIAN_POINT('',(-6.49999999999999,16.0257929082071,3.59824302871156));
#752=CARTESIAN_POINT('',(-6.49999999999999,16.1193048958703,3.65533489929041));
#753=CARTESIAN_POINT('',(-6.49999999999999,16.1687869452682,3.68012148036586));
#754=CARTESIAN_POINT('',(-6.49999999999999,16.2716394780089,3.71957198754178));
#755=CARTESIAN_POINT('',(-6.49999999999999,16.3250025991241,3.73425455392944));
#756=CARTESIAN_POINT('',(-6.49999999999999,16.4269596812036,3.75074988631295));
#757=CARTESIAN_POINT('',(-6.49999999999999,16.4753327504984,3.75392369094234));
#758=CARTESIAN_POINT('',(-6.49999999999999,16.571781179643,3.75088982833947));
#759=CARTESIAN_POINT('',(-6.49999999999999,16.6198565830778,3.74468356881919));
#760=CARTESIAN_POINT('',(-6.49999999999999,16.7084115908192,3.72478666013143));
#761=CARTESIAN_POINT('',(-6.49999999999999,16.7491169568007,3.71206829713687));
#762=CARTESIAN_POINT('',(-6.49999999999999,16.8281561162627,3.68071832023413));
#763=CARTESIAN_POINT('',(-6.49999999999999,16.8664893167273,3.66208523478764));
#764=CARTESIAN_POINT('',(-6.49999999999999,16.9575271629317,3.61006808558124));
#765=CARTESIAN_POINT('',(-6.49999999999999,17.008613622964,3.5738552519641));
#766=CARTESIAN_POINT('',(-6.49999999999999,17.1043814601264,3.49377752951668));
#767=CARTESIAN_POINT('',(-6.5,17.149046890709,3.44989416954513));
#768=CARTESIAN_POINT('',(-6.49999999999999,17.2566010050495,3.32963106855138));
#769=CARTESIAN_POINT('',(-6.49999999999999,17.3149418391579,3.24921629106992));
#770=CARTESIAN_POINT('',(-6.5,17.4190885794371,3.08073962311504));
#771=CARTESIAN_POINT('',(-6.50000000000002,17.4648647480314,2.99266022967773));
#772=CARTESIAN_POINT('',(-6.49999999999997,17.545739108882,2.81341823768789));
#773=CARTESIAN_POINT('',(-6.49999999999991,17.5809879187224,2.72232216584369));
#774=CARTESIAN_POINT('',(-6.50000000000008,17.6437177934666,2.53745293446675));
#775=CARTESIAN_POINT('',(-6.50000000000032,17.6711906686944,2.44367706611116));
#776=CARTESIAN_POINT('',(-6.49999999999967,17.7199426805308,2.25437631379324));
#777=CARTESIAN_POINT('',(-6.49999999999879,17.7412102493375,2.15884851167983));
#778=CARTESIAN_POINT('',(-6.5000000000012,17.7787344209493,1.96680386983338));
#779=CARTESIAN_POINT('',(-6.50000000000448,17.794989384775,1.87028671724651));
#780=CARTESIAN_POINT('',(-6.4999999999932,17.8308238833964,1.62686362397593));
#781=CARTESIAN_POINT('',(-6.49999999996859,17.8478111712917,1.47958130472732));
#782=CARTESIAN_POINT('',(-6.50000000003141,17.8752058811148,1.1843938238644));
#783=CARTESIAN_POINT('',(-6.5000000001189,17.8856107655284,1.03648844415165));
#784=CARTESIAN_POINT('',(-6.49999999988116,17.9015712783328,0.740511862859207));
#785=CARTESIAN_POINT('',(-6.49999999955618,17.9071296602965,0.592440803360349));
#786=CARTESIAN_POINT('',(-6.50000000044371,17.9144237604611,0.296246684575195));
#787=CARTESIAN_POINT('',(-6.50000000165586,17.9161603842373,0.148123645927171));
#788=CARTESIAN_POINT('',(-6.50000000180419,17.9161647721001,0.));
#789=B_SPLINE_CURVE_WITH_KNOTS('',3,(#663,#664,#665,#666,#667,#668,#669,#670,#671,#672,#673,
#674,#675,#676,#677,#678,#679,#680,#681,#682,#683,#684,#685,#686,#687,#688,#689,#690,#691,#692,
#693,#694,#695,#696,#697,#698,#699,#700,#701,#702,#703,#704,#705,#706,#707,#708,#709,#710,#711,
#712,#713,#714,#715,#716,#717,#718,#719,#720,#721,#722,#723,#724,#725,#726,#727,#728,#729,#730,
#731,#732,#733,#734,#735,#736,#737,#738,#739,#740,#741,#742,#743,#744,#745,#746,#747,#748,#749,
#750,#751,#752,#753,#754,#755,#756,#757,#758,#759,#760,#761,#762,#763,#764,#765,#766,#767,#768,
#769,#770,#771,#772,#773,#774,#775,#776,#777,#778,#779,#780,#781,#782,#783,#784,#785,#786,#787,
#788),.UNSPECIFIED.,.T.,.F.,(4,2,2,2,2,2,2,2,2,2,2,2,2,2,2,2,2,2,2,2,2,2,2,2,2,2,2,2,2,2,2,2,2,
2,2,2,2,2,2,2,2,2,2,2,2,2,2,2,2,2,2,2,2,2,2,2,2,2,2,2,2,2,4),(0.,0.553847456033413,
1.10803122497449,1.38581008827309,1.66356002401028,1.94101396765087,2.21839915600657,
2.50064095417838,2.78268528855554,3.06267257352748,3.34199729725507,3.56047429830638,
3.7785365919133,3.92890827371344,4.07918232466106,4.23095392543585,4.38257455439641,
4.51282785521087,4.64313014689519,4.80619619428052,4.96955932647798,5.20979375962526,
5.45048765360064,5.66533774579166,5.88037413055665,6.09596537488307,6.31145420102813,
6.66754668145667,7.02388391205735,7.38114482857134,7.73831800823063,8.09752640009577,
8.45675653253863,8.81546707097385,9.17416023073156,9.59650591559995,10.0190424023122,
10.4390909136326,10.8588435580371,11.2029497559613,11.5481602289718,11.8977472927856,
12.2453452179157,12.4084929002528,12.5716693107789,12.7367925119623,12.9016102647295,
13.0461521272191,13.1906722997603,13.3180953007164,13.4455500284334,13.6323448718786,
13.8195958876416,14.1159628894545,14.4130253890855,14.7056080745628,14.99849777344,
15.2919300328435,15.58545813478,16.0300038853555,16.4747209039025,16.9191850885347,
17.3635439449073),.UNSPECIFIED.);
#790=EDGE_CURVE('E99',#206,#570,#789,.T.);
#791=ORIENTED_EDGE('',*,*,#790,.T.);
#792=ORIENTED_EDGE('',*,*,#571,.T.);
#793=ORIENTED_EDGE('',*,*,#77,.T.);
#794=EDGE_LOOP('',(#662,#791,#792,#793));
#795=FACE_BOUND('',#794,.T.);
#796=ADVANCED_FACE('F154',(#795),#661,.F.);
#797=CARTESIAN_POINT('',(0.,16.5,0.));
#798=DIRECTION('',(0.,-1.,0.));
#799=DIRECTION('',(0.,0.,-1.));
#800=AXIS2_PLACEMENT_3D('',#797,#798,#799);
#801=TOROIDAL_SURFACE('',#800,6.00555349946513,1.5);
#802=CARTESIAN_POINT('',(0.,18.,0.));
#803=DIRECTION('',(0.,-1.,0.));
#804=DIRECTION('',(0.,0.,-1.));
#805=AXIS2_PLACEMENT_3D('',#802,#803,#804);
#806=CIRCLE('',#805,6.00555349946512);
#807=CARTESIAN_POINT('',(0.,18.,-6.00555349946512));
#808=VERTEX_POINT('',#807);
#809=EDGE_CURVE('E194',#808,#808,#806,.T.);
#810=ORIENTED_EDGE('',*,*,#809,.T.);
#811=EDGE_LOOP('',(#810));
#812=FACE_BOUND('',#811,.T.);
#813=ORIENTED_EDGE('',*,*,#309,.F.);
#814=ORIENTED_EDGE('',*,*,#456,.F.);
#815=ORIENTED_EDGE('',*,*,#553,.F.);
#816=ORIENTED_EDGE('',*,*,#650,.F.);
#817=ORIENTED_EDGE('',*,*,#790,.F.);
#818=ORIENTED_EDGE('',*,*,#207,.F.);
#819=EDGE_LOOP('',(#813,#814,#815,#816,#817,#818));
#820=FACE_BOUND('',#819,.T.);
#821=ADVANCED_FACE('F85',(#812,#820),#801,.T.);
#822=CARTESIAN_POINT('',(0.,18.,7.50555349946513));
#823=DIRECTION('',(0.,1.,0.));
#824=DIRECTION('',(0.,0.,1.));
#825=AXIS2_PLACEMENT_3D('',#822,#823,#824);
#826=PLANE('',#825);
#827=ORIENTED_EDGE('',*,*,#809,.F.);
#828=EDGE_LOOP('',(#827));
#829=FACE_BOUND('',#828,.T.);
#830=ADVANCED_FACE('F153',(#829),#826,.T.);
#831=CLOSED_SHELL('',(#46,#55,#114,#218,#315,#462,#559,#656,#796,#821,#830));
#832=MANIFOLD_SOLID_BREP('B2',#831);
#833=ADVANCED_BREP_SHAPE_REPRESENTATION('',(#18,#832),#14);
#834=SHAPE_DEFINITION_REPRESENTATION(#9,#833);
ENDSEC;
END-ISO-10303-21;
